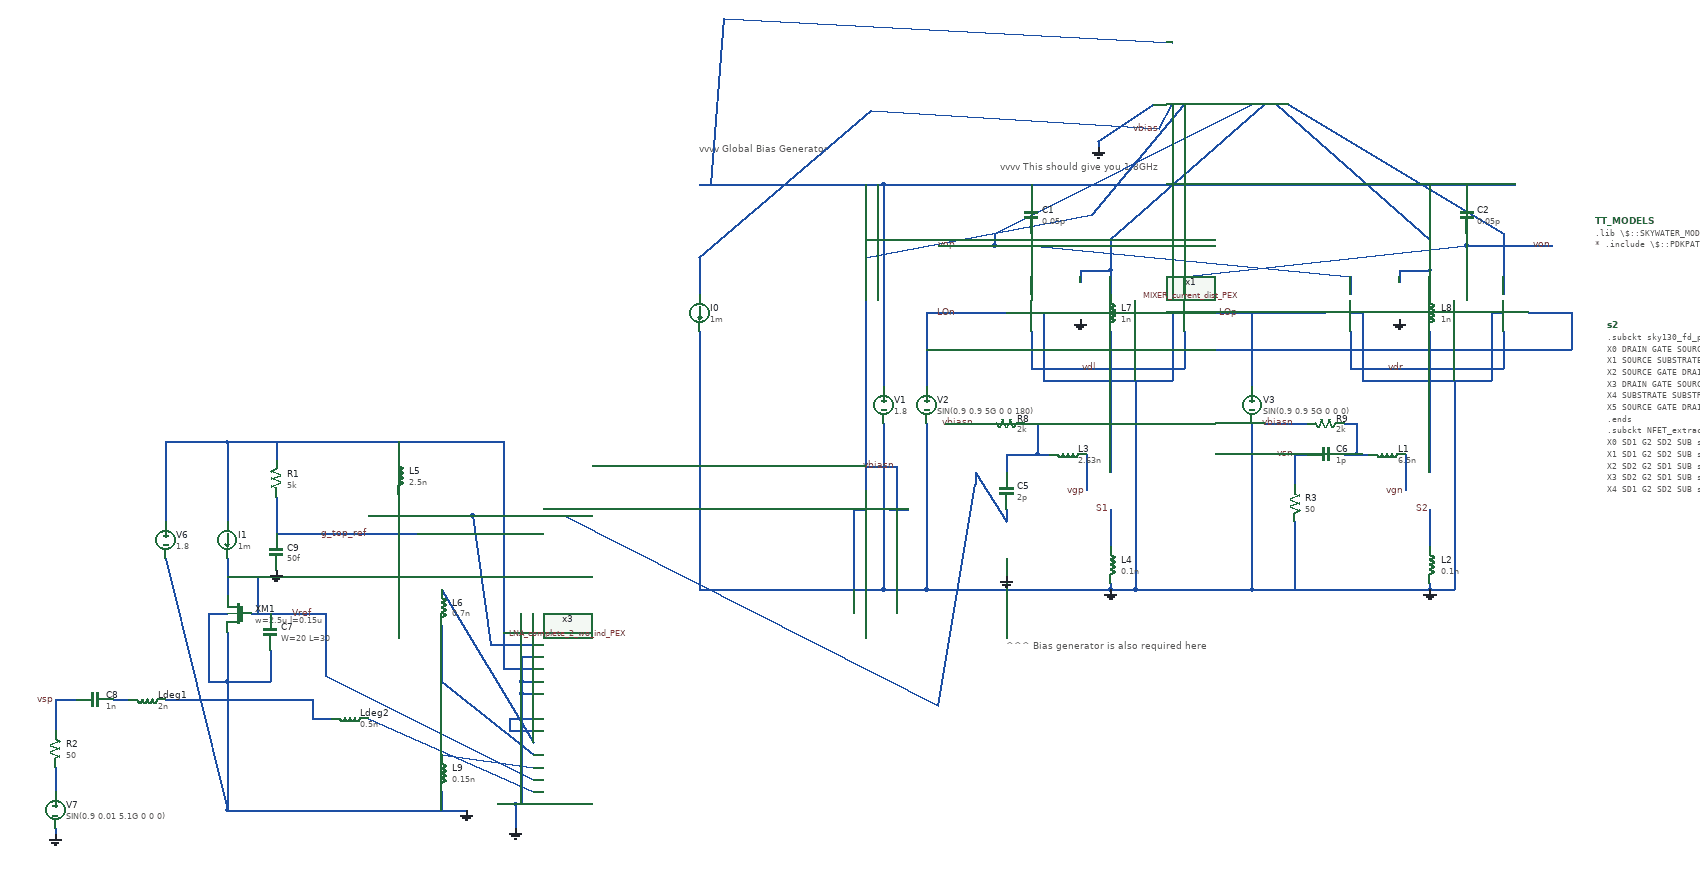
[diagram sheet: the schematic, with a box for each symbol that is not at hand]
v {xschem version=3.0.0 file_version=1.2 }
G {}
K {}
V {}
S {}
E {}
T {vvvv This should give you 1.8GHz} 550 -1250 0 0 0.4 0.4 {}
T {vvvv Global Bias Generator} 60 -1280 0 0 0.4 0.4 {}
T {^^^ Bias generator is also required here} 560 -470 0 0 0.4 0.4 {}
N 600 -970 600 -910 {
lab=vdl}
N 600 -910 850 -910 {
lab=vdl}
N 850 -970 850 -910 {
lab=vdl}
N 730 -810 730 -800 {
lab=vdl}
N 600 -1000 620 -1000 {
lab=GND}
N 620 -1000 620 -890 {
lab=GND}
N 730 -910 730 -870 {
lab=vdl}
N 620 -890 830 -890 {
lab=GND}
N 830 -1000 830 -890 {
lab=GND}
N 830 -1000 850 -1000 {
lab=GND}
N 770 -890 770 -770 {
lab=GND}
N 1370 -1130 1370 -1100 {
lab=von}
N 1310 -1130 1310 -1110 {
lab=von}
N 1310 -1110 1370 -1110 {
lab=von}
N 600 -1130 600 -1100 {
lab=vop}
N 540 -1130 540 -1110 {
lab=vop}
N 540 -1110 600 -1110 {
lab=vop}
N 540 -1210 850 -1210 {
lab=#net1}
N 1310 -1210 1310 -1190 {
lab=#net1}
N 600 -1210 600 -1190 {
lab=#net1}
N 360 -1140 360 -880 {
lab=#net1}
N 360 -1210 540 -1210 {
lab=#net1}
N 360 -820 360 -670 {
lab=GND}
N 430 -1000 430 -880 {
lab=LOn}
N 430 -1000 560 -1000 {
lab=LOn}
N 890 -1000 960 -1000 {
lab=LOp}
N 430 -820 430 -670 {
lab=GND}
N 1120 -970 1120 -910 {
lab=vdr}
N 1120 -910 1370 -910 {
lab=vdr}
N 1370 -970 1370 -910 {
lab=vdr}
N 1250 -810 1250 -800 {
lab=vdr}
N 1120 -1000 1140 -1000 {
lab=GND}
N 1140 -1000 1140 -890 {
lab=GND}
N 1250 -910 1250 -870 {
lab=vdr}
N 1140 -890 1350 -890 {
lab=GND}
N 1350 -1000 1350 -890 {
lab=GND}
N 1350 -1000 1370 -1000 {
lab=GND}
N 1290 -890 1290 -770 {
lab=GND}
N 1410 -1000 1480 -1000 {
lab=LOn}
N 960 -1000 1080 -1000 {
lab=LOp}
N 1480 -1000 1480 -940 {
lab=LOn}
N 430 -940 1480 -940 {
lab=LOn}
N 960 -1000 960 -880 {
lab=LOp}
N 960 -820 960 -670 {
lab=GND}
N 850 -1210 1370 -1210 {
lab=#net1}
N 1370 -1110 1450 -1110 {
lab=von}
N 1370 -1100 1370 -1030 {
lab=von}
N 600 -1100 600 -1030 {
lab=vop}
N 850 -1060 850 -1030 {
lab=von}
N 850 -1060 1310 -1110 {
lab=von}
N 1120 -1060 1120 -1030 {
lab=vop}
N 600 -1110 1120 -1060 {
lab=vop}
N 360 -1210 360 -1140 {
lab=#net1}
N 450 -1110 540 -1110 {
lab=vop}
N 1250 -560 1250 -550 {
lab=GND}
N 730 -560 730 -550 {
lab=GND}
N 510 -740 510 -720 {
lab=#net2}
N 610 -820 610 -770 {
lab=#net3}
N 610 -770 630 -770 {
lab=#net3}
N 1030 -740 1030 -720 {
lab=vsn}
N 1140 -770 1150 -770 {
lab=#net4}
N 770 -770 770 -710 {
lab=GND}
N 730 -680 730 -620 {
lab=S1}
N 770 -710 770 -550 {
lab=GND}
N 730 -550 770 -550 {
lab=GND}
N 690 -770 690 -710 {
lab=vgp}
N 1210 -770 1210 -710 {
lab=vgn}
N 1290 -770 1290 -710 {
lab=GND}
N 1250 -680 1250 -620 {
lab=S2}
N 1290 -710 1290 -550 {
lab=GND}
N 1250 -550 1290 -550 {
lab=GND}
N 1080 -550 1250 -550 {
lab=GND}
N 960 -670 960 -550 {
lab=GND}
N 960 -550 1080 -550 {
lab=GND}
N 560 -550 730 -550 {
lab=GND}
N 730 -550 770 -550 {
lab=GND}
N 770 -550 960 -550 {
lab=GND}
N 430 -670 430 -550 {
lab=GND}
N 430 -550 560 -550 {
lab=GND}
N 360 -670 360 -560 {
lab=GND}
N 360 -560 360 -550 {
lab=GND}
N 360 -550 430 -550 {
lab=GND}
N 730 -800 730 -740 {
lab=vdl}
N 1250 -800 1250 -740 {
lab=vdr}
N 680 -1070 680 -1050 {
lab=#net5}
N 680 -1070 730 -1070 {
lab=#net5}
N 730 -1070 730 -1030 {
lab=#net5}
N 730 -970 730 -910 {
lab=vdl}
N 730 -1120 730 -1070 {
lab=#net5}
N 1200 -1070 1200 -1050 {
lab=#net6}
N 1200 -1070 1250 -1070 {
lab=#net6}
N 1250 -1070 1250 -1030 {
lab=#net6}
N 1250 -970 1250 -910 {
lab=vdr}
N 1250 -1120 1250 -1070 {
lab=#net6}
N 1250 -1210 1250 -1180 {
lab=#net1}
N 730 -870 730 -810 {
lab=vdl}
N 1250 -870 1250 -810 {
lab=vdr}
N 150 -1210 360 -1210 {
lab=#net1}
N 60 -1090 60 -1030 {
lab=vbias}
N 60 -970 60 -550 {
lab=GND}
N 150 -550 360 -550 {
lab=GND}
N 330 -1120 350 -1120 {
lab=#net1}
N 350 -1210 350 -1120 {
lab=#net1}
N 330 -1210 330 -1150 {
lab=#net1}
N 330 -1090 330 -710 {
lab=vbiasn}
N 330 -750 380 -750 {
lab=vbiasn}
N 380 -750 380 -680 {
lab=vbiasn}
N 60 -1210 150 -1210 {
lab=#net1}
N 60 -550 150 -550 {
lab=GND}
N 590 -770 610 -770 {
lab=#net3}
N 590 -820 610 -820 {
lab=#net3}
N 460 -820 530 -820 {
lab=vbiasn}
N 330 -650 330 -550 {
lab=GND}
N 310 -680 330 -680 {
lab=GND}
N 310 -680 310 -550 {
lab=GND}
N 370 -680 400 -680 {
lab=vbiasn}
N 1130 -820 1130 -770 {
lab=#net4}
N 1130 -770 1150 -770 {
lab=#net4}
N 1030 -770 1050 -770 {
lab=vsn}
N 1030 -770 1030 -740 {
lab=vsn}
N 1110 -770 1130 -770 {
lab=#net4}
N 1110 -820 1130 -820 {
lab=#net4}
N 980 -820 1050 -820 {
lab=vbiasn}
N 1030 -560 1030 -550 {
lab=GND}
N 1370 -1210 1390 -1210 {
lab=#net1}
N -710 -600 -710 -540 {
lab=Vref}
N -710 -570 -660 -570 {
lab=Vref}
N -660 -570 -660 -510 {
lab=Vref}
N -480 -670 -350 -670 {
lab=#net2}
N -420 -640 -400 -640 {
lab=g_top_ref}
N -350 -670 -310 -670 {
lab=#net2}
N -740 -510 -740 -450 {
lab=GND}
N -740 -510 -710 -510 {
lab=GND}
N -710 -190 -640 -190 {
lab=GND}
N -895 -370 -870 -370 {
lab=#net7}
N -810 -370 -590 -370 {
lab=#net8}
N -360 -410 -360 -400 {
lab=#net9}
N -640 -190 -430 -190 {
lab=GND}
N -430 -705 -430 -670 {
lab=#net2}
N -430 -790 -430 -765 {
lab=#net10}
N -360 -490 -360 -410 {
lab=#net9}
N -460 -790 -280 -790 {
lab=#net10}
N -360 -220 -360 -190 {
lab=GND}
N -710 -360 -710 -190 {
lab=GND}
N -640 -450 -640 -400 {
lab=GND}
N -710 -400 -640 -400 {
lab=GND}
N -740 -450 -740 -400 {
lab=GND}
N -740 -400 -710 -400 {
lab=GND}
N -710 -790 -710 -660 {
lab=#net10}
N -670 -510 -550 -510 {
lab=Vref}
N -710 -790 -460 -790 {
lab=#net10}
N -710 -400 -710 -360 {
lab=GND}
N -710 -480 -710 -400 {
lab=GND}
N -430 -190 -320 -190 {
lab=GND}
N -250 -670 -160 -670 {
lab=#net2}
N -630 -700 -630 -640 {
lab=g_top_ref}
N -630 -790 -630 -760 {
lab=#net10}
N -630 -640 -560 -640 {
lab=g_top_ref}
N -240 -200 -240 -160 {
lab=GND}
N -240 -200 -210 -200 {
lab=GND}
N -360 -280 -210 -260 {
lab=#net11}
N -360 -400 -210 -280 {
lab=#net9}
N -570 -340 -540 -340 {
lab=#net8}
N -570 -370 -570 -340 {
lab=#net8}
N -480 -340 -210 -220 {
lab=#net12}
N -550 -510 -550 -410 {
lab=Vref}
N -550 -410 -210 -240 {
lab=Vref}
N -280 -790 -260 -790 {
lab=#net10}
N -260 -790 -260 -490 {
lab=#net10}
N -230 -440 -210 -440 {
lab=GND}
N -230 -440 -230 -400 {
lab=GND}
N -230 -400 -210 -400 {
lab=GND}
N -230 -400 -230 -380 {
lab=GND}
N -230 -380 -210 -380 {
lab=GND}
N -230 -380 -230 -200 {
lab=GND}
N -260 -420 -210 -420 {
lab=#net10}
N -260 -490 -260 -420 {
lab=#net10}
N -260 -480 -210 -480 {
lab=#net10}
N -310 -670 -280 -460 {
lab=#net2}
N -280 -460 -210 -460 {
lab=#net2}
N -270 -200 -240 -200 {
lab=GND}
N -590 -370 -570 -370 {
lab=#net8}
N -560 -640 -420 -640 {
lab=g_top_ref}
N -360 -550 -210 -300 {
lab=#net13}
N -250 -340 -210 -340 {
lab=#net14}
N -250 -340 -250 -320 {
lab=#net14}
N -250 -320 -210 -320 {
lab=#net14}
N -970 -370 -955 -370 {
lab=vsp}
N -990 -340 -990 -320 {
lab=vsp}
N -990 -260 -990 -220 {
lab=#net15}
N -990 -160 -990 -150 {
lab=GND}
N -990 -370 -970 -370 {
lab=vsp}
N -990 -370 -990 -340 {
lab=vsp}
N 1030 -660 1030 -550 {
lab=GND}
N 450 -360 510 -720 {
lab=#net2}
N -810 -790 -810 -660 {
lab=#net10}
N -810 -790 -710 -790 {
lab=#net10}
N -810 -600 -710 -190 {
lab=GND}
N 560 -600 560 -570 {
lab=GND}
N 560 -770 590 -770 {
lab=#net3}
N 560 -680 560 -660 {
lab=#net2}
N 560 -770 560 -740 {
lab=#net3}
N 510 -740 560 -660 {
lab=#net2}
N -310 -670 -250 -670 {
lab=#net2}
N 80 -1210 100 -1480 {
lab=#net1}
N 100 -1480 830 -1440 {
lab=#net1}
N 60 -1090 340 -1330 {
lab=vbias}
N 340 -1330 810 -1300 {
lab=vbias}
N 810 -1300 830 -1340 {
lab=vbias}
N 710 -1280 800 -1340 {
lab=GND}
N 710 -1280 710 -1270 {
lab=GND}
N 540 -1130 960 -1340 {
lab=vop}
N 730 -1120 980 -1340 {
lab=#net5}
N 1000 -1340 1250 -1120 {
lab=#net6}
N 1020 -1340 1370 -1130 {
lab=von}
N 700 -1160 850 -1340 {
lab=vbiasn}
N 330 -1090 700 -1160 {
lab=vbiasn}
N -160 -670 450 -360 {
lab=#net2}
C {devices/code_shown.sym} 1540 -980 0 0 {name=s2 only_toplevel=false value=".subckt sky130_fd_pr__rf_nfet_01v8_bM04W5p00L0p15_ext DRAIN GATE SOURCE SUBSTRATE
X0 DRAIN GATE SOURCE SUBSTRATE sky130_fd_pr__nfet_01v8 ad=2.828e+12p pd=2.132e+07u as=4.242e+12p ps=3.198e+07u w=5.05e+06u l=150000u
X1 SOURCE SUBSTRATE SUBSTRATE SUBSTRATE sky130_fd_pr__nfet_01v8 ad=0p pd=0u as=3.03e+12p ps=2.14e+07u w=5.05e+06u l=150000u
X2 SOURCE GATE DRAIN SUBSTRATE sky130_fd_pr__nfet_01v8 ad=0p pd=0u as=0p ps=0u w=5.05e+06u l=150000u
X3 DRAIN GATE SOURCE SUBSTRATE sky130_fd_pr__nfet_01v8 ad=0p pd=0u as=0p ps=0u w=5.05e+06u l=150000u
X4 SUBSTRATE SUBSTRATE SOURCE SUBSTRATE sky130_fd_pr__nfet_01v8 ad=0p pd=0u as=0p ps=0u w=5.05e+06u l=150000u
X5 SOURCE GATE DRAIN SUBSTRATE sky130_fd_pr__nfet_01v8 ad=0p pd=0u as=0p ps=0u w=5.05e+06u l=150000u
.ends

.subckt NFET_extract_1 SD1 SD2 G1 G2 SUB
X0 SD1 G2 SD2 SUB sky130_fd_pr__nfet_01v8 ad=0p pd=0u as=0p ps=0u w=5.05e+06u l=150000u
X1 SD1 G2 SD2 SUB sky130_fd_pr__nfet_01v8 ad=0p pd=0u as=0p ps=0u w=5.05e+06u l=150000u
X2 SD2 G2 SD1 SUB sky130_fd_pr__nfet_01v8 ad=0p pd=0u as=0p ps=0u w=5.05e+06u l=150000u
X3 SD2 G2 SD1 SUB sky130_fd_pr__nfet_01v8 ad=0p pd=0u as=0p ps=0u w=5.05e+06u l=150000u
X4 SD1 G2 SD2 SUB sky130_fd_pr__nfet_01v8 ad=0p pd=0u as=0p ps=0u w=5.05e+06u l=150000u
X5 SD1 G2 SD2 SUB sky130_fd_pr__nfet_01v8 ad=0p pd=0u as=0p ps=0u w=5.05e+06u l=150000u
X6 SD2 G2 SD1 SUB sky130_fd_pr__nfet_01v8 ad=0p pd=0u as=0p ps=0u w=5.05e+06u l=150000u
X7 SD2 G2 SD1 SUB sky130_fd_pr__nfet_01v8 ad=0p pd=0u as=0p ps=0u w=5.05e+06u l=150000u
X8 SD1 G2 SD2 SUB sky130_fd_pr__nfet_01v8 ad=0p pd=0u as=0p ps=0u w=5.05e+06u l=150000u
X9 SD1 G2 SD2 SUB sky130_fd_pr__nfet_01v8 ad=0p pd=0u as=0p ps=0u w=5.05e+06u l=150000u
X10 SD2 G2 SD1 SUB sky130_fd_pr__nfet_01v8 ad=0p pd=0u as=0p ps=0u w=5.05e+06u l=150000u
X11 SD2 G2 SD1 SUB sky130_fd_pr__nfet_01v8 ad=0p pd=0u as=0p ps=0u w=5.05e+06u l=150000u
C0 SUB SD1 3.04fF
C1 G2 SD2 3.72fF
C2 G2 SD1 4.78fF
C3 SD1 SD2 30.67fF
C4 G2 SUB 2.48fF
C5 G2 SUB 3.11fF 
C6 SD1 SUB 6.93fF
.ends

* Input Transconductance
XMEXT_0_0 vdl S1 vgp vgp GND NFET_extract_1
XMEXT_0_1 vdl S1 vgp vgp GND NFET_extract_1
XMEXT_1_0 vdr S2 vgn vgn GND NFET_extract_1
XMEXT_1_1 vdr S2 vgn vgn GND NFET_extract_1

* Current Source

XMEXT_IREF_0 vbiasn GND vbiasn vbiasn GND NFET_extract_1
XMEXT_IREF_1 vbiasn GND vbiasn vbiasn GND NFET_extract_1


* Switches
XMEXT_l1_0 vop vdl LOn LOn GND NFET_extract_1
XMEXT_l2_0 von vdl LOp LOp GND NFET_extract_1
XMEXT_r1_0 vop vdr LOp LOp GND NFET_extract_1
XMEXT_r2_0 von vdr LOn LOn GND NFET_extract_1

XMEXT_l1_1 vop vdl LOn LOn GND NFET_extract_1
XMEXT_l2_1 von vdl LOp LOp GND NFET_extract_1
XMEXT_r1_1 vop vdr LOp LOp GND NFET_extract_1
XMEXT_r2_1 von vdr LOn LOn GND NFET_extract_1
.options savecurrents

.tran 10ps 50ns
* .sp dec 1000 1e9 10e9 1
.control
run
display
*let m_start = 9
*let m_stop  = 14
*let m_delta = 1
let vo = v(vop)-v(von)
let vs = v(vsp)-v(vsn)
let vg = v(vgp)-v(vgn)

*let m_var = m_start
*while m_var le m_stop
*  print m_var
*  alter @m.xm1.msky130_fd_pr__pfet_01v8[m] = m_var
*  alter @m.xm3.msky130_fd_pr__pfet_01v8[m] = m_var
  
*  tran 10ps 50ns
*  * plot v(von) v(vop)
*  let vo = v(vop)-v(von)
plot @l7[i]
plot vo 
*  let m_var = m_var + m_delta
*end


* plot vo
plot vs
plot vg
* fft vo vs vg
* plot db(vo) db(vs)



.endc
"}
C {devices/code.sym} 1520 -1150 0 0 {name=TT_MODELS only_toplevel=false
format="tcleval(@value )" value=".lib \\\\$::SKYWATER_MODELS\\\\/sky130.lib.spice tt
* .include \\\\$::PDKPATH\\\\/libs.ref/sky130_fd_sc_hvl/spice/sky130_fd_sc_hvl.spice
"}
C {devices/gnd.sym} 730 -550 0 0 {name=l1 lab=GND}
C {devices/capa.sym} 600 -1160 0 0 {name=C1
m=1
value=0.05p
footprint=1206
device="ceramic capacitor"}
C {devices/capa.sym} 1310 -1160 0 0 {name=C2
m=1
value=0.05p
footprint=1206
device="ceramic capacitor"}
C {devices/vsource.sym} 360 -850 0 0 {name=V1 value=1.8
}
C {devices/vsource.sym} 430 -850 0 0 {name=V2 value="SIN(0.9 0.9 5G 0 0 180)"
}
C {devices/vsource.sym} 960 -850 0 0 {name=V3 value="SIN(0.9 0.9 5G 0 0 0)"
}
C {devices/lab_wire.sym} 480 -1000 0 0 {name=l2 sig_type=std_logic lab=LOn}
C {devices/lab_wire.sym} 940 -1000 0 0 {name=l3 sig_type=std_logic lab=LOp}
C {devices/lab_wire.sym} 1450 -1110 0 0 {name=l4 sig_type=std_logic lab=von}
C {devices/gnd.sym} 1250 -550 0 0 {name=l5 lab=GND}
C {devices/lab_wire.sym} 480 -1110 0 0 {name=l7 sig_type=std_logic lab=vop}
C {devices/ind.sym} 660 -770 1 0 {name=L3
m=1
value=2.63n
footprint=1206
device=inductor}
C {devices/ind.sym} 1180 -770 1 0 {name=L1
m=1
value=6.5n
footprint=1206
device=inductor}
C {devices/ind.sym} 1250 -590 0 0 {name=L2
m=1
value=0.1n
footprint=1206
device=inductor}
C {devices/ind.sym} 730 -590 0 0 {name=L4
m=1
value=0.1n
footprint=1206
device=inductor}
C {devices/ind.sym} 730 -1000 0 0 {name=L7
m=1
value=1n
footprint=1206
device=inductor}
C {devices/gnd.sym} 680 -990 0 0 {name=l8 lab=GND}
C {devices/ind.sym} 1250 -1000 0 0 {name=L8
m=1
value=1n
footprint=1206
device=inductor}
C {devices/gnd.sym} 1200 -990 0 0 {name=l9 lab=GND}
C {devices/lab_wire.sym} 690 -710 0 0 {name=l11 sig_type=std_logic lab=vgp}
C {devices/lab_wire.sym} 1030 -770 0 0 {name=l12 sig_type=std_logic lab=vsn}
C {devices/lab_wire.sym} 1210 -710 0 0 {name=l13 sig_type=std_logic lab=vgn}
C {devices/lab_wire.sym} 1210 -910 0 0 {name=l14 sig_type=std_logic lab=vdr}
C {devices/lab_wire.sym} 710 -910 0 0 {name=l15 sig_type=std_logic lab=vdl}
C {devices/isource.sym} 60 -1000 0 0 {name=I0 value=1m}
C {devices/lab_wire.sym} 810 -1300 0 0 {name=l6 sig_type=std_logic lab=vbias}
C {devices/lab_wire.sym} 730 -680 0 0 {name=l18 sig_type=std_logic lab=S1}
C {devices/lab_wire.sym} 1250 -680 0 0 {name=l20 sig_type=std_logic lab=S2}
C {devices/res.sym} 560 -820 1 0 {name=R8
value=2k
footprint=1206
device=resistor
m=1}
C {devices/lab_wire.sym} 380 -750 0 0 {name=l17 sig_type=std_logic lab=vbiasn}
C {devices/lab_wire.sym} 510 -820 0 0 {name=l19 sig_type=std_logic lab=vbiasn}
C {devices/capa.sym} 1080 -770 1 0 {name=C6
m=1
value=1p
footprint=1206
device="ceramic capacitor"}
C {devices/res.sym} 1080 -820 1 0 {name=R9
value=2k
footprint=1206
device=resistor
m=1}
C {devices/lab_wire.sym} 1030 -820 0 0 {name=l21 sig_type=std_logic lab=vbiasn}
C {devices/vsource.sym} -810 -630 0 0 {name=V6 value=1.8}
C {devices/isource.sym} -710 -630 0 0 {name=I1 value=1m}
C {devices/nmos4.sym} -690 -510 0 1 {name=XM1 model=sky130_fd_pr__rf_nfet_01v8_bM04W5p00L0p15_ext w=2.5u l=0.15u m=1}
C {sky130_fd_pr/cap_mim_m3_1.sym} -640 -480 0 0 {name=C7 model=cap_mim_m3_1 W=20 L=30 MF=1 spiceprefix=X}
C {devices/ind.sym} -430 -735 0 0 {name=L5
m=1
value=2.5n
footprint=1206
device=inductor}
C {devices/capa.sym} -925 -370 1 0 {name=C8
m=1
value=1n
footprint=1206
device="ceramic capacitor"}
C {devices/ind.sym} -840 -370 1 0 {name=Ldeg1
m=1
value=2n
footprint=1206
device=inductor}
C {devices/ind.sym} -360 -520 0 0 {name=L6
m=1
value=0.7n
footprint=1206
device=inductor}
C {devices/ind.sym} -510 -340 1 0 {name=Ldeg2
m=1
value=0.5n
footprint=1206
device=inductor}
C {devices/ind.sym} -360 -250 0 0 {name=L9
m=1
value=0.15n
footprint=1206
device=inductor}
C {devices/lab_wire.sym} -570 -510 0 0 {name=l26 sig_type=std_logic lab=Vref}
C {devices/res.sym} -630 -730 2 0 {name=R1
value=5k

footprint=1206
device=resistor
m=1}
C {devices/capa.sym} -630 -610 2 1 {name=C9
m=1
value=50f
footprint=1206
device="ceramic capacitor"}
C {LNA_complete_2_wo_ind_PEX.sym} -60 -340 0 1 {name=x3}
C {devices/lab_wire.sym} -480 -640 0 0 {name=l31 sig_type=std_logic lab=g_top_ref}
C {devices/vsource.sym} -990 -190 0 0 {name=V7 value="SIN(0.9 0.01 5.1G 0 0 0)"
}
C {devices/res.sym} -990 -290 0 0 {name=R2
value=50
footprint=1206
device=resistor
m=1}
C {devices/lab_wire.sym} -990 -370 0 0 {name=l27 sig_type=std_logic lab=vsp}
C {devices/gnd.sym} -990 -150 0 0 {name=l10 lab=GND}
C {devices/gnd.sym} -320 -190 0 0 {name=l22 lab=GND}
C {devices/gnd.sym} -240 -160 0 0 {name=l23 lab=GND}
C {devices/gnd.sym} -630 -580 0 0 {name=l24 lab=GND}
C {devices/gnd.sym} 560 -570 0 0 {name=l25 lab=GND}
C {devices/capa.sym} 560 -710 0 0 {name=C5
m=1
value=2p
footprint=1206
device="ceramic capacitor"}
C {devices/res.sym} 1030 -690 0 0 {name=R3
value=50
footprint=1206
device=resistor
m=1}
C {MIXER_current_dist_PEX.sym} 920 -1340 0 0 {name=x1}
C {devices/gnd.sym} 710 -1270 0 0 {name=l28 lab=GND}
